VERSION 5.8 ;
BUSBITCHARS "[]" ;
DIVIDERCHAR "/" ;

# ==============================================================================
# SANITIZED MACRO DISTRIBUTION LEF — 100% Internal Hardware IP Black-Boxed
# Sub-blocks 01, 03, 05 completely stripped of all internal polygon geometry.
# ==============================================================================
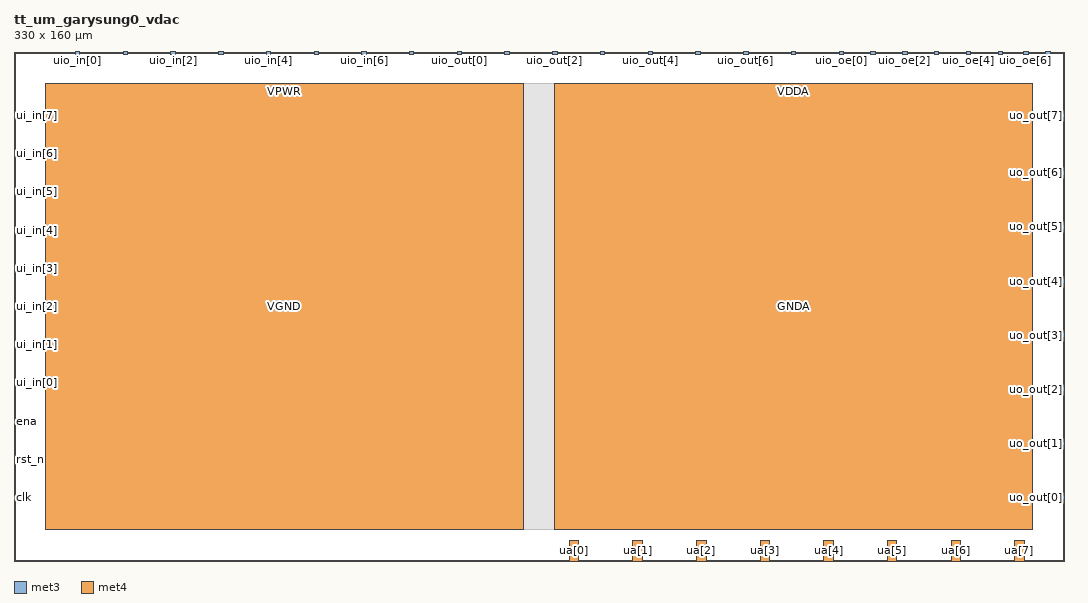
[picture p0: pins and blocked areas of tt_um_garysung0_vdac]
MACRO tt_um_garysung0_vdac
  CLASS BLOCK ;
  ORIGIN 0.000 0.000 ;
  SIZE 330.000 BY 160.000 ;
  SYMMETRY X Y ;
  SITE unithd ;

  PIN clk
    DIRECTION INPUT ;
    USE SIGNAL ;
    PORT
      LAYER met3 ;
      RECT 0.000 19.300 0.700 20.700 ;
    END
  END clk

  PIN rst_n
    DIRECTION INPUT ;
    USE SIGNAL ;
    PORT
      LAYER met3 ;
      RECT 0.000 31.300 0.700 32.700 ;
    END
  END rst_n

  PIN ena
    DIRECTION INPUT ;
    USE SIGNAL ;
    PORT
      LAYER met3 ;
      RECT 0.000 43.300 0.700 44.700 ;
    END
  END ena

  PIN ui_in[0]
    DIRECTION INPUT ;
    USE SIGNAL ;
    PORT
      LAYER met3 ;
      RECT 0.000 55.300 0.700 56.700 ;
    END
  END ui_in[0]

  PIN ui_in[1]
    DIRECTION INPUT ;
    USE SIGNAL ;
    PORT
      LAYER met3 ;
      RECT 0.000 67.300 0.700 68.700 ;
    END
  END ui_in[1]

  PIN ui_in[2]
    DIRECTION INPUT ;
    USE SIGNAL ;
    PORT
      LAYER met3 ;
      RECT 0.000 79.300 0.700 80.700 ;
    END
  END ui_in[2]

  PIN ui_in[3]
    DIRECTION INPUT ;
    USE SIGNAL ;
    PORT
      LAYER met3 ;
      RECT 0.000 91.300 0.700 92.700 ;
    END
  END ui_in[3]

  PIN ui_in[4]
    DIRECTION INPUT ;
    USE SIGNAL ;
    PORT
      LAYER met3 ;
      RECT 0.000 103.300 0.700 104.700 ;
    END
  END ui_in[4]

  PIN ui_in[5]
    DIRECTION INPUT ;
    USE SIGNAL ;
    PORT
      LAYER met3 ;
      RECT 0.000 115.300 0.700 116.700 ;
    END
  END ui_in[5]

  PIN ui_in[6]
    DIRECTION INPUT ;
    USE SIGNAL ;
    PORT
      LAYER met3 ;
      RECT 0.000 127.300 0.700 128.700 ;
    END
  END ui_in[6]

  PIN ui_in[7]
    DIRECTION INPUT ;
    USE SIGNAL ;
    PORT
      LAYER met3 ;
      RECT 0.000 139.300 0.700 140.700 ;
    END
  END ui_in[7]

  PIN uo_out[0]
    DIRECTION OUTPUT ;
    USE SIGNAL ;
    PORT
      LAYER met3 ;
      RECT 329.300 19.300 330.000 20.700 ;
    END
  END uo_out[0]

  PIN uo_out[1]
    DIRECTION OUTPUT ;
    USE SIGNAL ;
    PORT
      LAYER met3 ;
      RECT 329.300 36.300 330.000 37.700 ;
    END
  END uo_out[1]

  PIN uo_out[2]
    DIRECTION OUTPUT ;
    USE SIGNAL ;
    PORT
      LAYER met3 ;
      RECT 329.300 53.300 330.000 54.700 ;
    END
  END uo_out[2]

  PIN uo_out[3]
    DIRECTION OUTPUT ;
    USE SIGNAL ;
    PORT
      LAYER met3 ;
      RECT 329.300 70.300 330.000 71.700 ;
    END
  END uo_out[3]

  PIN uo_out[4]
    DIRECTION OUTPUT ;
    USE SIGNAL ;
    PORT
      LAYER met3 ;
      RECT 329.300 87.300 330.000 88.700 ;
    END
  END uo_out[4]

  PIN uo_out[5]
    DIRECTION OUTPUT ;
    USE SIGNAL ;
    PORT
      LAYER met3 ;
      RECT 329.300 104.300 330.000 105.700 ;
    END
  END uo_out[5]

  PIN uo_out[6]
    DIRECTION OUTPUT ;
    USE SIGNAL ;
    PORT
      LAYER met3 ;
      RECT 329.300 121.300 330.000 122.700 ;
    END
  END uo_out[6]

  PIN uo_out[7]
    DIRECTION OUTPUT ;
    USE SIGNAL ;
    PORT
      LAYER met3 ;
      RECT 329.300 139.300 330.000 140.700 ;
    END
  END uo_out[7]

  PIN uio_in[0]
    DIRECTION INOUT ;
    USE SIGNAL ;
    PORT
      LAYER met3 ;
      RECT 19.300 159.300 20.700 160.000 ;
    END
  END uio_in[0]

  PIN uio_in[1]
    DIRECTION INOUT ;
    USE SIGNAL ;
    PORT
      LAYER met3 ;
      RECT 34.300 159.300 35.700 160.000 ;
    END
  END uio_in[1]

  PIN uio_in[2]
    DIRECTION INOUT ;
    USE SIGNAL ;
    PORT
      LAYER met3 ;
      RECT 49.300 159.300 50.700 160.000 ;
    END
  END uio_in[2]

  PIN uio_in[3]
    DIRECTION INOUT ;
    USE SIGNAL ;
    PORT
      LAYER met3 ;
      RECT 64.300 159.300 65.700 160.000 ;
    END
  END uio_in[3]

  PIN uio_in[4]
    DIRECTION INOUT ;
    USE SIGNAL ;
    PORT
      LAYER met3 ;
      RECT 79.300 159.300 80.700 160.000 ;
    END
  END uio_in[4]

  PIN uio_in[5]
    DIRECTION INOUT ;
    USE SIGNAL ;
    PORT
      LAYER met3 ;
      RECT 94.300 159.300 95.700 160.000 ;
    END
  END uio_in[5]

  PIN uio_in[6]
    DIRECTION INOUT ;
    USE SIGNAL ;
    PORT
      LAYER met3 ;
      RECT 109.300 159.300 110.700 160.000 ;
    END
  END uio_in[6]

  PIN uio_in[7]
    DIRECTION INOUT ;
    USE SIGNAL ;
    PORT
      LAYER met3 ;
      RECT 124.300 159.300 125.700 160.000 ;
    END
  END uio_in[7]

  PIN uio_out[0]
    DIRECTION INOUT ;
    USE SIGNAL ;
    PORT
      LAYER met3 ;
      RECT 139.300 159.300 140.700 160.000 ;
    END
  END uio_out[0]

  PIN uio_out[1]
    DIRECTION INOUT ;
    USE SIGNAL ;
    PORT
      LAYER met3 ;
      RECT 154.300 159.300 155.700 160.000 ;
    END
  END uio_out[1]

  PIN uio_out[2]
    DIRECTION INOUT ;
    USE SIGNAL ;
    PORT
      LAYER met3 ;
      RECT 169.300 159.300 170.700 160.000 ;
    END
  END uio_out[2]

  PIN uio_out[3]
    DIRECTION INOUT ;
    USE SIGNAL ;
    PORT
      LAYER met3 ;
      RECT 184.300 159.300 185.700 160.000 ;
    END
  END uio_out[3]

  PIN uio_out[4]
    DIRECTION INOUT ;
    USE SIGNAL ;
    PORT
      LAYER met3 ;
      RECT 199.300 159.300 200.700 160.000 ;
    END
  END uio_out[4]

  PIN uio_out[5]
    DIRECTION INOUT ;
    USE SIGNAL ;
    PORT
      LAYER met3 ;
      RECT 214.300 159.300 215.700 160.000 ;
    END
  END uio_out[5]

  PIN uio_out[6]
    DIRECTION INOUT ;
    USE SIGNAL ;
    PORT
      LAYER met3 ;
      RECT 229.300 159.300 230.700 160.000 ;
    END
  END uio_out[6]

  PIN uio_out[7]
    DIRECTION INOUT ;
    USE SIGNAL ;
    PORT
      LAYER met3 ;
      RECT 244.300 159.300 245.700 160.000 ;
    END
  END uio_out[7]

  PIN uio_oe[0]
    DIRECTION INOUT ;
    USE SIGNAL ;
    PORT
      LAYER met3 ;
      RECT 259.300 159.300 260.700 160.000 ;
    END
  END uio_oe[0]

  PIN uio_oe[1]
    DIRECTION INOUT ;
    USE SIGNAL ;
    PORT
      LAYER met3 ;
      RECT 269.300 159.300 270.700 160.000 ;
    END
  END uio_oe[1]

  PIN uio_oe[2]
    DIRECTION INOUT ;
    USE SIGNAL ;
    PORT
      LAYER met3 ;
      RECT 279.300 159.300 280.700 160.000 ;
    END
  END uio_oe[2]

  PIN uio_oe[3]
    DIRECTION INOUT ;
    USE SIGNAL ;
    PORT
      LAYER met3 ;
      RECT 289.300 159.300 290.700 160.000 ;
    END
  END uio_oe[3]

  PIN uio_oe[4]
    DIRECTION INOUT ;
    USE SIGNAL ;
    PORT
      LAYER met3 ;
      RECT 299.300 159.300 300.700 160.000 ;
    END
  END uio_oe[4]

  PIN uio_oe[5]
    DIRECTION INOUT ;
    USE SIGNAL ;
    PORT
      LAYER met3 ;
      RECT 309.300 159.300 310.700 160.000 ;
    END
  END uio_oe[5]

  PIN uio_oe[6]
    DIRECTION INOUT ;
    USE SIGNAL ;
    PORT
      LAYER met3 ;
      RECT 317.300 159.300 318.700 160.000 ;
    END
  END uio_oe[6]

  PIN uio_oe[7]
    DIRECTION INOUT ;
    USE SIGNAL ;
    PORT
      LAYER met3 ;
      RECT 324.300 159.300 325.700 160.000 ;
    END
  END uio_oe[7]

  PIN ua[0]
    DIRECTION INOUT ;
    USE ANALOG ;
    PORT
      LAYER met4 ;
      RECT 174.500 0.000 177.500 6.500 ;
    END
  END ua[0]

  PIN ua[1]
    DIRECTION INOUT ;
    USE ANALOG ;
    PORT
      LAYER met4 ;
      RECT 194.500 0.000 197.500 6.500 ;
    END
  END ua[1]

  PIN ua[2]
    DIRECTION INOUT ;
    USE ANALOG ;
    PORT
      LAYER met4 ;
      RECT 214.500 0.000 217.500 6.500 ;
    END
  END ua[2]

  PIN ua[3]
    DIRECTION INOUT ;
    USE ANALOG ;
    PORT
      LAYER met4 ;
      RECT 234.500 0.000 237.500 6.500 ;
    END
  END ua[3]

  PIN ua[4]
    DIRECTION INOUT ;
    USE ANALOG ;
    PORT
      LAYER met4 ;
      RECT 254.500 0.000 257.500 6.500 ;
    END
  END ua[4]

  PIN ua[5]
    DIRECTION INOUT ;
    USE ANALOG ;
    PORT
      LAYER met4 ;
      RECT 274.500 0.000 277.500 6.500 ;
    END
  END ua[5]

  PIN ua[6]
    DIRECTION INOUT ;
    USE ANALOG ;
    PORT
      LAYER met4 ;
      RECT 294.500 0.000 297.500 6.500 ;
    END
  END ua[6]

  PIN ua[7]
    DIRECTION INOUT ;
    USE ANALOG ;
    PORT
      LAYER met4 ;
      RECT 314.500 0.000 317.500 6.500 ;
    END
  END ua[7]

  PIN VPWR
    DIRECTION INOUT ;
    USE POWER ;
    PORT
      LAYER met4 ;
      RECT 10.000 10.000 160.000 150.000 ;
    END
  END VPWR

  PIN VGND
    DIRECTION INOUT ;
    USE GROUND ;
    PORT
      LAYER met4 ;
      RECT 10.000 10.000 160.000 150.000 ;
    END
  END VGND

  PIN VDDA
    DIRECTION INOUT ;
    USE POWER ;
    PORT
      LAYER met4 ;
      RECT 170.000 10.000 320.000 150.000 ;
    END
  END VDDA

  PIN GNDA
    DIRECTION INOUT ;
    USE GROUND ;
    PORT
      LAYER met4 ;
      RECT 170.000 10.000 320.000 150.000 ;
    END
  END GNDA

  OBS
    LAYER met1 ;
      RECT 10.000 10.000 320.000 150.000 ;
    LAYER met2 ;
      RECT 10.000 10.000 320.000 150.000 ;
    LAYER met3 ;
      RECT 10.000 10.000 320.000 150.000 ;
    LAYER met4 ;
      RECT 10.000 10.000 320.000 150.000 ;
    LAYER met5 ;
      RECT 10.000 10.000 320.000 150.000 ;
  END
END tt_um_garysung0_vdac
END LIBRARY
